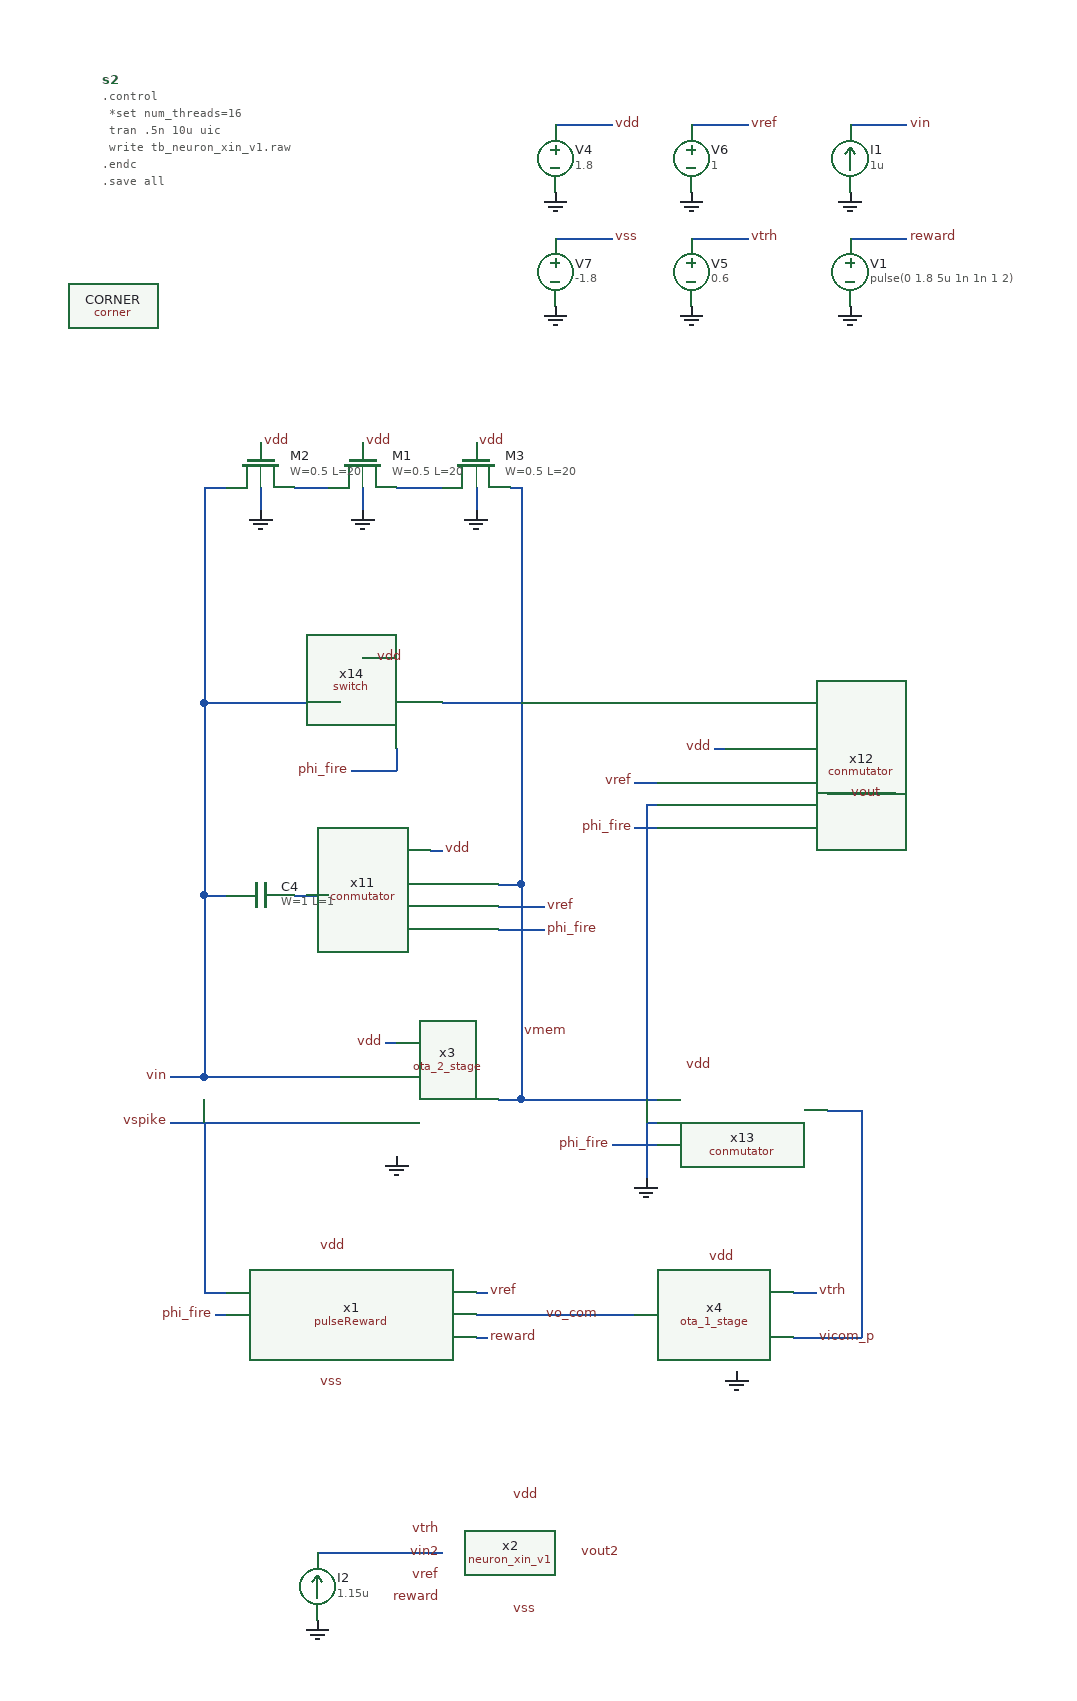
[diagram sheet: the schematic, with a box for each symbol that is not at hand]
v {xschem version=3.4.7 file_version=1.2}
G {}
K {}
V {}
S {}
E {}
B 2 560 330 1360 730 {flags=graph
y1=0.58
y2=1.7
ypos1=0
ypos2=2
divy=5
subdivy=1
unity=1
x1=1.1581099e-06
x2=2.5002865e-06
divx=5
subdivx=1


dataset=-1
unitx=1
logx=0
logy=0
color=6
node=vout2
linewidth_mult=2}
B 2 560 -820 1360 -420 {flags=graph

y2=1.8
ypos1=0
ypos2=2
divy=5
subdivy=1
unity=1
x1=1.1581099e-06
x2=2.5002865e-06
divx=5
subdivx=1


dataset=-1
unitx=1
logx=0
logy=0
color=7
node=vmem
y1=0
linewidth_mult=2}
B 2 560 -1220 1360 -820 {flags=graph
y1=0

ypos1=0
ypos2=2
divy=5
subdivy=1
unity=1
x1=1.1581099e-06
x2=2.5002865e-06
divx=5
subdivx=1


dataset=-1
unitx=1
logx=0
logy=0
color=4
node=vspike
y2=1.8
linewidth_mult=2}
B 2 560 -70 1360 330 {flags=graph
y2=1.7
ypos1=0
ypos2=2
divy=5
subdivy=1
unity=1
x1=1.1581099e-06
x2=2.5002865e-06
divx=5
subdivx=1


dataset=-1
unitx=1
logx=0
logy=0

color=12
node=vout
y1=0.58
linewidth_mult=2}
B 2 -1280 -520 -480 -120 {flags=graph
y1=-0.03
y2=1.1
ypos1=0
ypos2=2
divy=5
subdivy=1
unity=1
x1=1.1581099e-06
x2=2.5002865e-06
divx=5
subdivx=1


dataset=-1
unitx=1
logx=0
logy=0


color="4 5"
node="vicom_p
vtrh"
linewidth_mult=2}
B 2 -1330 20 -530 420 {flags=graph
y1=4.9e-05
y2=1.9
ypos1=0
ypos2=2
divy=5
subdivy=1
unity=1
x1=1.1581099e-06
x2=2.5002865e-06
divx=5
subdivx=1


dataset=-1
unitx=1
logx=0
logy=0



color=6
node=vo_com
linewidth_mult=2}
B 2 -1330 420 -530 820 {flags=graph
y1=-0.096
y2=1.9
ypos1=0
ypos2=2
divy=5
subdivy=1
unity=1
x1=1.1581099e-06
x2=2.5002865e-06
divx=5
subdivx=1


dataset=-1
unitx=1
logx=0
logy=0




color=8
node=phi_fire
linewidth_mult=2}
B 2 -1280 -920 -480 -520 {flags=graph
y1=0
y2=1.8
ypos1=0
ypos2=2
divy=5
subdivy=1
unity=1
x1=1.1581099e-06
x2=2.5002865e-06
divx=5
subdivx=1


dataset=-1
unitx=1
logx=0
logy=0


color=6
node=reward
linewidth_mult=2}
B 2 1360 -820 2160 -420 {flags=graph
y1=0
y2=1.8
ypos1=0
ypos2=2
divy=5
subdivy=1
unity=1
x1=1.1581099e-06
x2=2.5002865e-06
divx=5
subdivx=1


dataset=-1
unitx=1
logx=0
logy=0
color=12
node=vout
linewidth_mult=2}
B 2 1360 -1220 2160 -820 {flags=graph
y1=0
y2=1.8
ypos1=0
ypos2=2
divy=5
subdivy=1
unity=1
x1=1.1581099e-06
x2=2.5002865e-06
divx=5
subdivx=1


dataset=-1
unitx=1
logx=0
logy=0

color=10
node=vin
linewidth_mult=2}
B 2 -2130 420 -1330 820 {flags=graph
y1=0.54699548
y2=0.7140697
ypos1=0
ypos2=2
divy=5
subdivy=1
unity=1
x1=1.1581099e-06
x2=2.5002865e-06
divx=5
subdivx=1


dataset=-1
unitx=1
logx=0
logy=0


color="4 5"
node="vicom_p
vtrh"
linewidth_mult=2}
B 2 -2130 20 -1330 420 {flags=graph
y1=0
y2=1.8
ypos1=0
ypos2=2
divy=5
subdivy=1
unity=1
x1=1.1581099e-06
x2=2.5002865e-06
divx=5
subdivx=1


dataset=-1
unitx=1
logx=0
logy=0


color=12
node=reward
linewidth_mult=2}
B 2 1360 110 2160 510 {flags=graph
y1=-1.1
y2=0.98
ypos1=0
ypos2=2
divy=5
subdivy=1
unity=1
x1=1.1581099e-06
x2=2.5002865e-06
divx=5
subdivx=1


dataset=-1
unitx=1
logx=0
logy=0
color=7
node="vout vout2 -"
linewidth_mult=2}
N 100 -380 150 -380 {
lab=vdd}
N 360 -380 410 -380 {
lab=vin}
N 220 -280 270 -280 {
lab=vtrh}
N 220 -380 270 -380 {
lab=vref}
N 100 -280 150 -280 {
lab=vss}
N 360 -280 410 -280 {
lab=reward}
N 140 670 170 670 {
lab=vo_com}
N 170 240 190 240 {
lab=phi_fire}
N 170 200 190 200 {
lab=vref}
N 340 210 360 210 {
lab=vout}
N -50 430 -40 430 {
lab=vdd}
N -10 260 0 260 {
lab=vdd}
N 50 310 90 310 {
lab=vref}
N 50 290 70 290 {
lab=vmem}
N 50 330 90 330 {
lab=phi_fire}
N -130 300 -100 300 {
lab=#net1}
N 70 20 70 290 {
lab=vmem}
N -210 130 -210 300 {
lab=vin}
N -210 300 -190 300 {
lab=vin}
N -210 20 -210 130 {
lab=vin}
N -40 170 -40 190 {
lab=phi_fire}
N -80 190 -40 190 {
lab=phi_fire}
N 70 290 70 480 {
lab=vmem}
N -210 300 -210 460 {
lab=vin}
N -210 460 -90 460 {
lab=vin}
N -240 460 -210 460 {
lab=vin}
N 170 520 190 520 {
lab=phi_fire}
N 0 130 70 130 {
lab=vmem}
N -210 130 -90 130 {
lab=vin}
N -70 90 -60 90 {
lab=vdd}
N 360 210 400 210 {
lab=vout}
N 50 480 70 480 {
lab=vmem}
N 240 170 250 170 {
lab=vdd}
N -240 500 -90 500 {
lab=vspike}
N -210 500 -210 600 {
lab=vspike}
N 30 670 140 670 {
lab=vo_com}
N 30 650 40 650 {
lab=vref}
N -200 670 -190 670 {
lab=phi_fire}
N -210 -20 -210 20 {
lab=vin}
N 70 -20 70 20 {
lab=vmem}
N 30 690 40 690 {
lab=reward}
N -210 650 -190 650 {
lab=vspike}
N -210 600 -210 650 {
lab=vspike}
N 180 220 190 220 {
lab=vmem}
N 180 220 180 480 {
lab=vmem}
N 310 650 330 650 {
lab=vtrh}
N 340 490 360 490 {
lab=vicom_p}
N 370 490 370 690 {
lab=vicom_p}
N 360 490 370 490 {
lab=vicom_p}
N 310 690 370 690 {
lab=vicom_p}
N 70 480 190 480 {
lab=vmem}
N 150 520 170 520 {
lab=phi_fire}
N 180 500 180 550 {
lab=GND}
N 180 500 190 500 {
lab=GND}
N 30 -60 30 -40 {
lab=GND}
N -210 -60 -210 -20 {
lab=vin}
N 70 -60 70 -20 {
lab=vmem}
N -70 -60 -70 -40 {
lab=GND}
N -160 -60 -160 -40 {
lab=GND}
N -210 -60 -190 -60 {lab=vin}
N -130 -60 -100 -60 {lab=#net2}
N -40 -60 0 -60 {lab=#net3}
N 60 -60 70 -60 {lab=vmem}
N -110 880 -60 880 {
lab=vin2}
N -60 880 -0 880 {lab=vin2}
C {devices/code_shown.sym} -300 -420 0 0 {name=s2 only_toplevel=false value="
.control
 *set num_threads=16
 tran .5n 10u uic
 write tb_neuron_xin_v1.raw
.endc
.save all" }
C {devices/gnd.sym} 360 -320 0 0 {name=l8 lab=GND}
C {devices/vsource.sym} 100 -350 0 0 {name=V4 value=1.8}
C {devices/gnd.sym} 100 -320 0 0 {name=l9 lab=GND}
C {devices/lab_wire.sym} 150 -380 0 1 {name=p61 sig_type=std_logic lab=vdd}
C {devices/lab_wire.sym} 410 -380 0 1 {name=p62 sig_type=std_logic lab=vin}
C {devices/vsource.sym} 220 -250 0 0 {name=V5 value=0.6}
C {devices/gnd.sym} 220 -220 0 0 {name=l10 lab=GND}
C {devices/lab_wire.sym} 270 -280 0 1 {name=p63 sig_type=std_logic lab=vtrh}
C {devices/vsource.sym} 220 -350 0 0 {name=V6 value=1}
C {devices/gnd.sym} 220 -320 0 0 {name=l11 lab=GND}
C {devices/lab_wire.sym} 270 -380 0 1 {name=p64 sig_type=std_logic lab=vref}
C {devices/isource.sym} 360 -350 2 1 {name=I1 value=1u}
C {devices/vsource.sym} 100 -250 0 0 {name=V7 value=-1.8}
C {devices/gnd.sym} 100 -220 0 0 {name=l13 lab=GND}
C {devices/lab_wire.sym} 150 -280 0 1 {name=p72 sig_type=std_logic lab=vss}
C {devices/vsource.sym} 360 -250 0 0 {name=V1 value="pulse(0 1.8 5u 1n 1n 1 2)"}
C {devices/gnd.sym} 360 -220 0 0 {name=l2 lab=GND}
C {devices/lab_wire.sym} 410 -280 0 1 {name=p5 sig_type=std_logic lab=reward}
C {devices/lab_wire.sym} -110 610 0 1 {name=p48 sig_type=std_logic lab=vdd}
C {devices/lab_wire.sym} 140 670 0 0 {name=p49 sig_type=std_logic lab=vo_com}
C {devices/lab_wire.sym} 330 650 0 1 {name=p50 sig_type=std_logic lab=vtrh}
C {devices/lab_wire.sym} 260 620 0 0 {name=p51 sig_type=std_logic lab=vdd}
C {devices/lab_wire.sym} -240 500 0 0 {name=p52 sig_type=std_logic lab=vspike}
C {devices/lab_wire.sym} 170 240 0 0 {name=p53 sig_type=std_logic lab=phi_fire}
C {devices/lab_wire.sym} 170 200 0 0 {name=p54 sig_type=std_logic lab=vref}
C {devices/lab_wire.sym} -50 430 0 0 {name=p55 sig_type=std_logic lab=vdd}
C {devices/lab_wire.sym} 240 170 0 0 {name=p56 sig_type=std_logic lab=vdd}
C {devices/lab_wire.sym} 0 260 0 1 {name=p57 sig_type=std_logic lab=vdd}
C {devices/lab_wire.sym} 90 330 0 1 {name=p58 sig_type=std_logic lab=phi_fire}
C {devices/lab_wire.sym} -80 190 0 0 {name=p59 sig_type=std_logic lab=phi_fire}
C {devices/lab_wire.sym} 70 420 0 1 {name=p60 sig_type=std_logic lab=vmem}
C {devices/lab_wire.sym} -240 460 0 0 {name=p65 sig_type=std_logic lab=vin}
C {devices/lab_wire.sym} 330 690 2 0 {name=p66 sig_type=std_logic lab=vicom_p}
C {/foss/designs/spike_130/designs/subcells/core_conmutator/conmutator.sym} 50 360 0 1 {name=x11}
C {/foss/designs/spike_130/designs/subcells/core_conmutator/conmutator.sym} 190 270 0 0 {name=x12}
C {devices/lab_wire.sym} 150 520 0 0 {name=p67 sig_type=std_logic lab=phi_fire}
C {devices/lab_wire.sym} 240 450 0 0 {name=p68 sig_type=std_logic lab=vdd}
C {/foss/designs/spike_130/designs/subcells/core_conmutator/conmutator.sym} 190 550 0 0 {name=x13}
C {devices/gnd.sym} 180 550 0 0 {name=l12 lab=GND}
C {/foss/designs/spike_130/designs/subcells/core_switch/switch.sym} -110 190 0 0 {name=x14}
C {devices/lab_wire.sym} -60 90 0 1 {name=p69 sig_type=std_logic lab=vdd}
C {devices/lab_wire.sym} 390 210 0 0 {name=p70 sig_type=std_logic lab=vout}
C {devices/lab_wire.sym} 90 310 0 1 {name=p71 sig_type=std_logic lab=vref}
C {devices/gnd.sym} 260 720 0 1 {name=l14 lab=GND}
C {devices/lab_wire.sym} 40 650 0 1 {name=p1 sig_type=std_logic lab=vref}
C {devices/lab_wire.sym} -200 670 2 1 {name=p2 sig_type=std_logic lab=phi_fire}
C {sky130_fd_pr/cap_mim_m3_2.sym} -160 300 3 0 {name=C4 model=cap_mim_m3_2 W=1 L=1 MF=200 spiceprefix=X}
C {devices/lab_wire.sym} -110 730 0 1 {name=p3 sig_type=std_logic lab=vss}
C {devices/gnd.sym} -40 530 0 1 {name=l1 lab=GND}
C {/foss/designs/spike_130/designs/subcells/core_pulseReward/pulseReward.sym} -80 660 0 1 {name=x1}
C {devices/lab_wire.sym} 40 690 0 1 {name=p6 sig_type=std_logic lab=reward}
C {/foss/designs/spike_130/designs/subcells/core_ota_2stage/ota_2_stage.sym} -40 480 0 0 {name=x3}
C {/foss/designs/spike_130/designs/core_xin_neuron_v1/neuron_xin_v1.sym} 60 880 0 0 {name=x2}
C {devices/lab_wire.sym} 60 830 0 1 {name=p7 sig_type=std_logic lab=vdd}
C {devices/lab_wire.sym} 0 860 0 0 {name=p8 sig_type=std_logic lab=vtrh}
C {devices/lab_wire.sym} 0 880 0 0 {name=p9 sig_type=std_logic lab=vin2}
C {devices/lab_wire.sym} 0 900 0 0 {name=p10 sig_type=std_logic lab=vref}
C {devices/lab_wire.sym} 0 920 0 0 {name=p11 sig_type=std_logic lab=reward}
C {devices/lab_wire.sym} 60 930 2 0 {name=p12 sig_type=std_logic lab=vss}
C {devices/lab_wire.sym} 120 880 0 1 {name=p13 sig_type=std_logic lab=vout2}
C {launcher.sym} 760 -220 0 0 {name=h5
descr="load waves" 
tclcommand="xschem raw_read $netlist_dir/tb_neuron_xin_v1.raw tran"
}
C {sky130_fd_pr/corner.sym} -290 -220 0 0 {name=CORNER only_toplevel=true corner=tt}
C {sky130_fd_pr/nfet_01v8.sym} 30 -80 1 0 {name=M3
L=20
W=0.5
nf=1 mult=1
model=nfet_01v8
spiceprefix=X
}
C {devices/gnd.sym} 30 -40 0 0 {name=l17 lab=GND}
C {devices/lab_wire.sym} 30 -100 0 1 {name=p4 sig_type=std_logic lab=vdd}
C {sky130_fd_pr/nfet_01v8.sym} -70 -80 1 0 {name=M1
L=20
W=0.5
nf=1 mult=1
model=nfet_01v8
spiceprefix=X
}
C {devices/gnd.sym} -70 -40 0 0 {name=l3 lab=GND}
C {devices/lab_wire.sym} -70 -100 0 1 {name=p14 sig_type=std_logic lab=vdd}
C {sky130_fd_pr/nfet_01v8.sym} -160 -80 1 0 {name=M2
L=20
W=0.5
nf=1 mult=1
model=nfet_01v8
spiceprefix=X
}
C {devices/gnd.sym} -160 -40 0 0 {name=l4 lab=GND}
C {devices/lab_wire.sym} -160 -100 0 1 {name=p15 sig_type=std_logic lab=vdd}
C {devices/gnd.sym} -110 940 0 0 {name=l5 lab=GND}
C {devices/isource.sym} -110 910 2 1 {name=I2 value=1.15u}
C {/foss/designs/spike_130/designs/subcells/core_ota_1stage/ota_1_stage.sym} 260 670 0 1 {name=x4}
